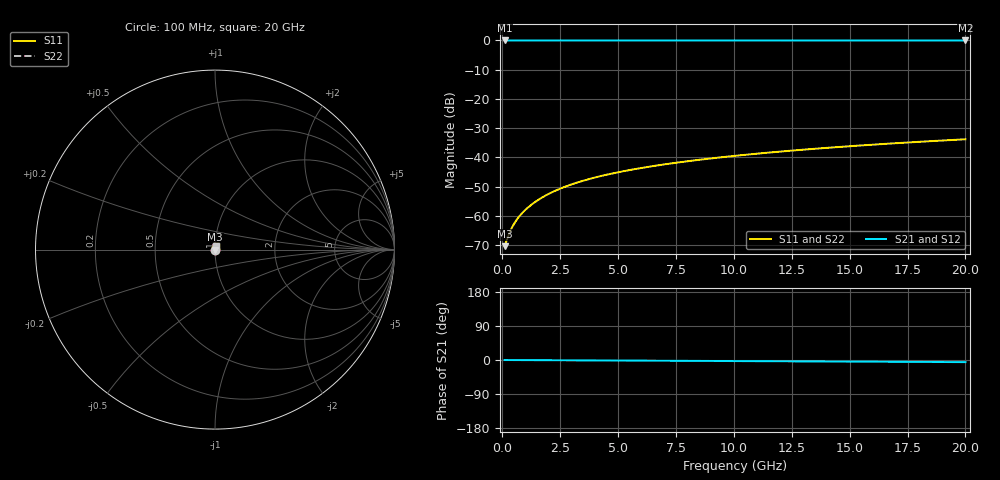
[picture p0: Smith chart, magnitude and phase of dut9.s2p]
! Touchstone file exported from HFSS 2026.1.0
!  File:  C:/ffzhzh/LocalFiles/Ansys_Project_Files/temp_test_TSV_9_1782978146_45748.aedt
!  Generated:  03:44:04 PM Jul  2, 2026
!  Design:  TSV
!  Project:  temp_test_TSV_9_1782978146_45748
! Variables:
!  h_bsmrdl = 2um
!  h_ox = 20um
!  h_rdl = 5um
!  h_sub = 54.53um
!  h_tmrdl = 5um
!  h_tsv = 54.53um
!  h_via = 3um
!  l_bsmrdl = 300um
!  l_sub = 410.38um
!  l_tmrdl = 200um
!  m_sub = 200um
!  pitch = 27.32um
!  r_tsv = 5.19um
!  s_tmrdl = 10um
!  w_bsmrdl = 18um
!  w_sub = 500um
!  w_tmrdl = 12um
!  x_tsv_center1 = 206um
!  x_tsv_center2 = 524um
!  x_tsv_center3 = 736um
!  x_tsv_center4 = 1054um
!  x_tsv_center5 = 1266um
!  x_tsv_center6 = 1584um
# GHz S MA R 50.000000
! Terminal data exported
! Port[1] = TSV1_1_T1
! Port[2] = TSV1_1_T2
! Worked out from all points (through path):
!   200 points, 100 MHz to 20 GHz, reference 50 ohm
!   highest |S21| = 0.00 dB at 100 MHz (marker M1); lowest = 0.0 dB at 20 GHz (marker M2)
!   lowest |S11| = -70.4 dB at 100 MHz (marker M3), VSWR 1.00, Z = 50 + j0.0139 ohm
!   |S11| at or under -10 dB: start of sweep to end of sweep
!   |S22| runs from -70.4 to -33.8 dB; largest |S21 - S12| = 2.5e-15
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0.1  0.0003033 27.3  0.9997 -0.0  0.9997 -0.0  0.0003033 27.3
! Gamma 0 0 0 0
! Port Impedance 50 0 50 0
0.3  0.0005008 53.4  0.9997 -0.1  0.9997 -0.1  0.0005008 53.4
0.4  0.0006119 58.9  0.9997 -0.1  0.9997 -0.1  0.0006119 58.9
0.5  0.0007225 62.6  0.9997 -0.1  0.9997 -0.1  0.0007225 62.6
0.6  0.0008322 65.4  0.9997 -0.2  0.9997 -0.2  0.0008322 65.4
0.8  0.001051 69.3  0.9996 -0.2  0.9996 -0.2  0.001051 69.3
1  0.001269 72.0  0.9996 -0.3  0.9996 -0.3  0.001269 72.0
1.2  0.001489 73.9  0.9996 -0.3  0.9996 -0.3  0.001489 73.9
1.4  0.00171 75.4  0.9996 -0.4  0.9996 -0.4  0.00171 75.4
1.7  0.002042 76.9  0.9995 -0.5  0.9995 -0.5  0.002042 76.9
2.2  0.002593 78.5  0.9995 -0.6  0.9995 -0.6  0.002593 78.5
2.8  0.003248 79.5  0.9994 -0.8  0.9994 -0.8  0.003248 79.5
3.5  0.004 80.1  0.9994 -1.0  0.9994 -1.0  0.004 80.1
4.2  0.004738 80.4  0.9993 -1.2  0.9993 -1.2  0.004738 80.4
5  0.005567 80.7  0.9992 -1.4  0.9992 -1.4  0.005567 80.7
5.9  0.006487 80.9  0.9991 -1.7  0.9991 -1.7  0.006487 80.9
6.8  0.007397 81.0  0.9991 -1.9  0.9991 -1.9  0.007397 81.0
8.3  0.008899 81.2  0.999 -2.4  0.999 -2.4  0.008899 81.2
10.1  0.01069 81.2  0.9988 -2.9  0.9988 -2.9  0.01069 81.2
13.4  0.01396 81.0  0.9986 -3.8  0.9986 -3.8  0.01396 81.0
16.7  0.0172 80.6  0.9984 -4.7  0.9984 -4.7  0.0172 80.6
20  0.02042 80.0  0.9982 -5.6  0.9982 -5.6  0.02042 80.0
